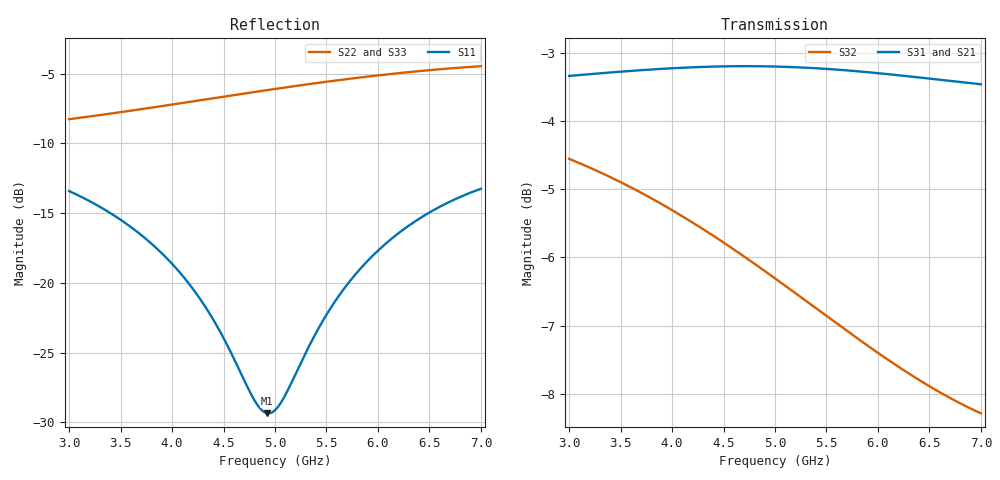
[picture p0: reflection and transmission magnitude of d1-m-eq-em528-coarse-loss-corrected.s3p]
! yapnr Order 0 prediction d1-m-eq-em528-coarse: predictions/D1/variants/d1-star-m-eq-em528/coarse_dense.s3p, loss-corrected
! substrate M-eq-em528; coupon model OSHPARK-4L-EM528; correction: ratio (port line)
! |S21|, |S31| (and S12, S13) scaled, phases kept; 50 ohm, e^(+jwt)
# GHz S RI R 50
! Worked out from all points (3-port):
!   161 points, 3 GHz to 7 GHz, reference 50 ohm
!   strongest paths, dB at 3 GHz, 4 GHz, 5 GHz, 6 GHz, 7 GHz:
!     S31: -3.3, -3.2, -3.2, -3.3, -3.5
!     S21: -3.3, -3.2, -3.2, -3.3, -3.5
!     S32: -4.6, -5.3, -6.3, -7.4, -8.3
!   lowest |S11| = -29.4 dB at 4.925 GHz (marker M1), VSWR 1.07, Z = 46.7 + j0.489 ohm
!   |S11| at or under -10 dB: start of sweep to end of sweep
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3  -0.1483 0.1535  0.0854 -0.6757  0.0854 -0.6757
   0.0853 -0.6757  0.0748 0.379  -0.1734 -0.566
   0.0853 -0.6757  -0.1734 -0.566  0.0748 0.379
3.575  -0.0936 0.131  -0.1101 -0.6778  -0.1101 -0.6778
       -0.1102 -0.6777  0.2169 0.3516  -0.341 -0.4511
       -0.1102 -0.6777  -0.341 -0.4511  0.2169 0.3516
4.05  -0.0575 0.0957  -0.2695 -0.6355  -0.2695 -0.6355
      -0.2695 -0.6354  0.3288 0.2904  -0.4331 -0.3227
      -0.2695 -0.6354  -0.4331 -0.3227  0.3288 0.2904
4.35  -0.0421 0.0671  -0.3639 -0.5883  -0.3639 -0.5883
      -0.3639 -0.5882  0.3915 0.2342  -0.4672 -0.2347
      -0.3639 -0.5882  -0.4672 -0.2347  0.3915 0.2342
4.925  -0.0336 0.00522  -0.5193 -0.4576  -0.5193 -0.4576
       -0.5193 -0.4576  0.4822 0.0939  -0.4834 -0.0687
       -0.5193 -0.4576  -0.4834 -0.0687  0.4822 0.0939
5  -0.0348 -0.00292  -0.5364 -0.4372  -0.5364 -0.4372
   -0.5364 -0.4371  0.4905 0.073  -0.4813 -0.0484
   -0.5364 -0.4371  -0.4813 -0.0484  0.4905 0.073
5.5  -0.0557 -0.0529  -0.6272 -0.2859  -0.6272 -0.2859
     -0.6271 -0.2858  0.5209 -0.0752  -0.4478 0.0747
     -0.6271 -0.2858  -0.4478 0.0747  0.5209 -0.0752
5.875  -0.0847 -0.0811  -0.6666 -0.1607  -0.6666 -0.1607
       -0.6665 -0.1607  0.5137 -0.1904  -0.4062 0.1503
       -0.6665 -0.1607  -0.4062 0.1503  0.5137 -0.1904
6.375  -0.1346 -0.0996  -0.6796 0.0107  -0.6796 0.0107
       -0.6795 0.0108  0.4644 -0.3363  -0.3387 0.2284
       -0.6795 0.0108  -0.3387 0.2284  0.4644 -0.3363
7  -0.1997 -0.0861  -0.6362 0.2154  -0.6362 0.2154
   -0.636 0.2154  0.3489 -0.4863  -0.2475 0.295
   -0.636 0.2154  -0.2475 0.295  0.3489 -0.4863
